VERSION 5.8 ;
BUSBITCHARS "[]" ;
DIVIDERCHAR "/" ;
UNITS
  DATABASE MICRONS 1000 ;
END UNITS
MANUFACTURINGGRID 0.005 ;

# Synthetic stack for the enclosure-edge pre-screen tests. Every name and value is invented.
# V1 states two checked rules (class VA: OPPOSITE NOCONCAVECORNER, class VB: OPPOSITE) and one
# form that is not checked (WRONGDIRECTION); V2 names a cut class it does not define.

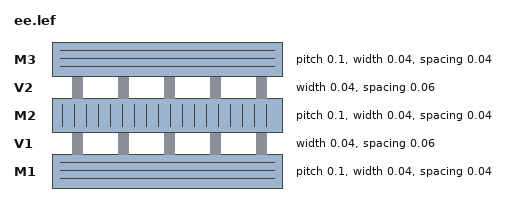
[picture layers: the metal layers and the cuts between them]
LAYER M1
  TYPE ROUTING ;
  DIRECTION HORIZONTAL ;
  PITCH 0.1 ;
  WIDTH 0.04 ;
  SPACING 0.04 ;
END M1

LAYER V1
  TYPE CUT ;
  WIDTH 0.04 ;
  SPACING 0.06 ;
  PROPERTY LEF58_CUTCLASS "CUTCLASS VA WIDTH 0.04 ; CUTCLASS VB WIDTH 0.04 LENGTH 0.08 ;" ;
  PROPERTY LEF58_ENCLOSUREEDGE "
    ENCLOSUREEDGE CUTCLASS VA ABOVE 0.02 OPPOSITE NOCONCAVECORNER 0.05 ;
    ENCLOSUREEDGE CUTCLASS VB ABOVE 0.01 OPPOSITE ;
    ENCLOSUREEDGE CUTCLASS VA ABOVE 0.02 OPPOSITE WRONGDIRECTION ; " ;
END V1

LAYER M2
  TYPE ROUTING ;
  DIRECTION VERTICAL ;
  PITCH 0.1 ;
  WIDTH 0.04 ;
  SPACING 0.04 ;
END M2

LAYER V2
  TYPE CUT ;
  WIDTH 0.04 ;
  SPACING 0.06 ;
  PROPERTY LEF58_ENCLOSUREEDGE "ENCLOSUREEDGE CUTCLASS VC ABOVE 0.02 OPPOSITE ;" ;
END V2

LAYER M3
  TYPE ROUTING ;
  DIRECTION HORIZONTAL ;
  PITCH 0.1 ;
  WIDTH 0.04 ;
  SPACING 0.04 ;
END M3

VIA VA12 DEFAULT
  LAYER M1 ;
    RECT -0.02 -0.02 0.02 0.02 ;
  LAYER V1 ;
    RECT -0.02 -0.02 0.02 0.02 ;
  LAYER M2 ;
    RECT -0.02 -0.02 0.02 0.02 ;
END VA12

VIA VB12 DEFAULT
  LAYER M1 ;
    RECT -0.02 -0.04 0.02 0.04 ;
  LAYER V1 ;
    RECT -0.02 -0.04 0.02 0.04 ;
  LAYER M2 ;
    RECT -0.03 -0.04 0.04 0.04 ;
END VB12

VIA VAOUT DEFAULT
  LAYER M1 ;
    RECT -0.02 -0.02 0.02 0.02 ;
  LAYER V1 ;
    RECT -0.02 -0.02 0.02 0.02 ;
  LAYER M2 ;
    RECT -0.02 -0.02 0.0 0.02 ;
END VAOUT

END LIBRARY
